VERSION 5.8 ;
BUSBITCHARS "[]" ;
DIVIDERCHAR "/" ;
UNITS
    DATABASE MICRONS 1000 ;
END UNITS

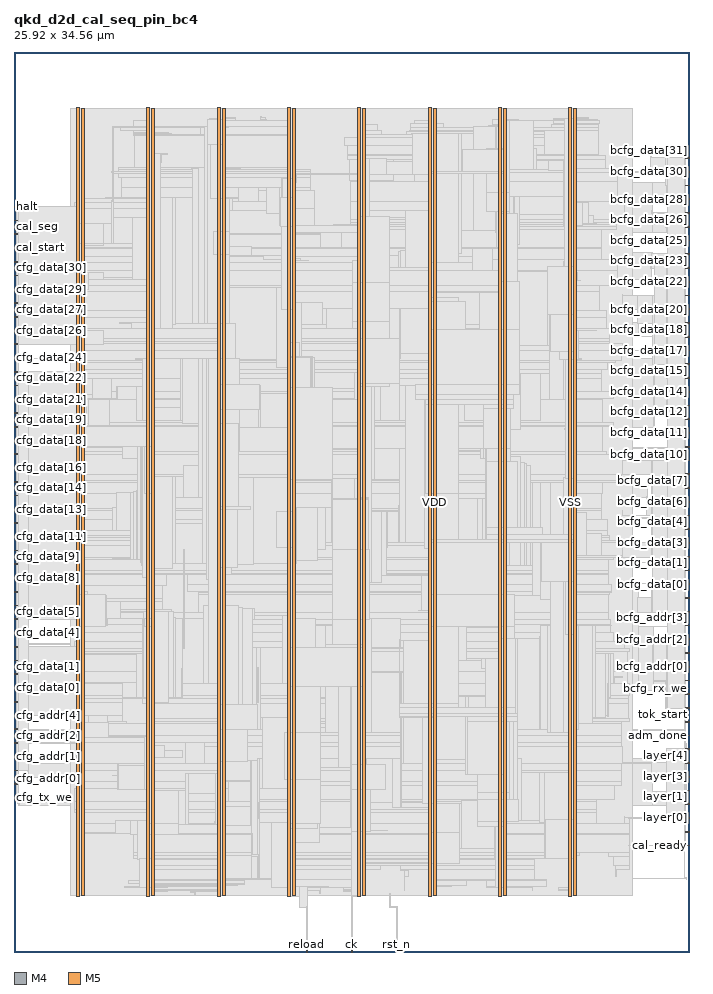
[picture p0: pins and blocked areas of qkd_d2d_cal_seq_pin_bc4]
MACRO qkd_d2d_cal_seq_pin_bc4
  FOREIGN qkd_d2d_cal_seq_pin_bc4 0 0 ;
  CLASS BLOCK ;
  SIZE 25.92 BY 34.56 ;
  PIN adm_done
    DIRECTION OUTPUT ;
    USE SIGNAL ;
    PORT
      LAYER M4 ;
        RECT  25.776 8.304 25.92 8.328 ;
    END
  END adm_done
  PIN bcfg_addr[0]
    DIRECTION INPUT ;
    USE SIGNAL ;
    PORT
      LAYER M4 ;
        RECT  25.776 10.944 25.92 10.968 ;
    END
  END bcfg_addr[0]
  PIN bcfg_addr[1]
    DIRECTION INPUT ;
    USE SIGNAL ;
    PORT
      LAYER M4 ;
        RECT  25.776 11.472 25.92 11.496 ;
    END
  END bcfg_addr[1]
  PIN bcfg_addr[2]
    DIRECTION INPUT ;
    USE SIGNAL ;
    PORT
      LAYER M4 ;
        RECT  25.776 12 25.92 12.024 ;
    END
  END bcfg_addr[2]
  PIN bcfg_addr[3]
    DIRECTION INPUT ;
    USE SIGNAL ;
    PORT
      LAYER M4 ;
        RECT  25.776 12.528 25.92 12.552 ;
    END
  END bcfg_addr[3]
  PIN bcfg_addr[4]
    DIRECTION INPUT ;
    USE SIGNAL ;
    PORT
      LAYER M4 ;
        RECT  25.776 13.056 25.92 13.08 ;
    END
  END bcfg_addr[4]
  PIN bcfg_addr[5]
    DIRECTION INPUT ;
    USE SIGNAL ;
    PORT
      LAYER M4 ;
        RECT  25.776 13.584 25.92 13.608 ;
    END
  END bcfg_addr[5]
  PIN bcfg_data[0]
    DIRECTION INPUT ;
    USE SIGNAL ;
    PORT
      LAYER M4 ;
        RECT  25.776 14.112 25.92 14.136 ;
    END
  END bcfg_data[0]
  PIN bcfg_data[10]
    DIRECTION INPUT ;
    USE SIGNAL ;
    PORT
      LAYER M4 ;
        RECT  25.776 19.392 25.92 19.416 ;
    END
  END bcfg_data[10]
  PIN bcfg_data[11]
    DIRECTION INPUT ;
    USE SIGNAL ;
    PORT
      LAYER M4 ;
        RECT  25.776 19.92 25.92 19.944 ;
    END
  END bcfg_data[11]
  PIN bcfg_data[12]
    DIRECTION INPUT ;
    USE SIGNAL ;
    PORT
      LAYER M4 ;
        RECT  25.776 20.448 25.92 20.472 ;
    END
  END bcfg_data[12]
  PIN bcfg_data[13]
    DIRECTION INPUT ;
    USE SIGNAL ;
    PORT
      LAYER M4 ;
        RECT  25.776 20.976 25.92 21 ;
    END
  END bcfg_data[13]
  PIN bcfg_data[14]
    DIRECTION INPUT ;
    USE SIGNAL ;
    PORT
      LAYER M4 ;
        RECT  25.776 21.504 25.92 21.528 ;
    END
  END bcfg_data[14]
  PIN bcfg_data[15]
    DIRECTION INPUT ;
    USE SIGNAL ;
    PORT
      LAYER M4 ;
        RECT  25.776 22.032 25.92 22.056 ;
    END
  END bcfg_data[15]
  PIN bcfg_data[16]
    DIRECTION INPUT ;
    USE SIGNAL ;
    PORT
      LAYER M4 ;
        RECT  25.776 22.56 25.92 22.584 ;
    END
  END bcfg_data[16]
  PIN bcfg_data[17]
    DIRECTION INPUT ;
    USE SIGNAL ;
    PORT
      LAYER M4 ;
        RECT  25.776 23.088 25.92 23.112 ;
    END
  END bcfg_data[17]
  PIN bcfg_data[18]
    DIRECTION INPUT ;
    USE SIGNAL ;
    PORT
      LAYER M4 ;
        RECT  25.776 23.616 25.92 23.64 ;
    END
  END bcfg_data[18]
  PIN bcfg_data[19]
    DIRECTION INPUT ;
    USE SIGNAL ;
    PORT
      LAYER M4 ;
        RECT  25.776 24.144 25.92 24.168 ;
    END
  END bcfg_data[19]
  PIN bcfg_data[1]
    DIRECTION INPUT ;
    USE SIGNAL ;
    PORT
      LAYER M4 ;
        RECT  25.776 14.64 25.92 14.664 ;
    END
  END bcfg_data[1]
  PIN bcfg_data[20]
    DIRECTION INPUT ;
    USE SIGNAL ;
    PORT
      LAYER M4 ;
        RECT  25.776 24.672 25.92 24.696 ;
    END
  END bcfg_data[20]
  PIN bcfg_data[21]
    DIRECTION INPUT ;
    USE SIGNAL ;
    PORT
      LAYER M4 ;
        RECT  25.776 25.2 25.92 25.224 ;
    END
  END bcfg_data[21]
  PIN bcfg_data[22]
    DIRECTION INPUT ;
    USE SIGNAL ;
    PORT
      LAYER M4 ;
        RECT  25.776 25.728 25.92 25.752 ;
    END
  END bcfg_data[22]
  PIN bcfg_data[23]
    DIRECTION INPUT ;
    USE SIGNAL ;
    PORT
      LAYER M4 ;
        RECT  25.776 26.256 25.92 26.28 ;
    END
  END bcfg_data[23]
  PIN bcfg_data[24]
    DIRECTION INPUT ;
    USE SIGNAL ;
    PORT
      LAYER M4 ;
        RECT  25.776 26.784 25.92 26.808 ;
    END
  END bcfg_data[24]
  PIN bcfg_data[25]
    DIRECTION INPUT ;
    USE SIGNAL ;
    PORT
      LAYER M4 ;
        RECT  25.776 27.312 25.92 27.336 ;
    END
  END bcfg_data[25]
  PIN bcfg_data[26]
    DIRECTION INPUT ;
    USE SIGNAL ;
    PORT
      LAYER M4 ;
        RECT  25.776 27.84 25.92 27.864 ;
    END
  END bcfg_data[26]
  PIN bcfg_data[27]
    DIRECTION INPUT ;
    USE SIGNAL ;
    PORT
      LAYER M4 ;
        RECT  25.776 28.368 25.92 28.392 ;
    END
  END bcfg_data[27]
  PIN bcfg_data[28]
    DIRECTION INPUT ;
    USE SIGNAL ;
    PORT
      LAYER M4 ;
        RECT  25.776 28.896 25.92 28.92 ;
    END
  END bcfg_data[28]
  PIN bcfg_data[29]
    DIRECTION INPUT ;
    USE SIGNAL ;
    PORT
      LAYER M4 ;
        RECT  25.776 29.424 25.92 29.448 ;
    END
  END bcfg_data[29]
  PIN bcfg_data[2]
    DIRECTION INPUT ;
    USE SIGNAL ;
    PORT
      LAYER M4 ;
        RECT  25.776 15.168 25.92 15.192 ;
    END
  END bcfg_data[2]
  PIN bcfg_data[30]
    DIRECTION INPUT ;
    USE SIGNAL ;
    PORT
      LAYER M4 ;
        RECT  25.776 29.952 25.92 29.976 ;
    END
  END bcfg_data[30]
  PIN bcfg_data[31]
    DIRECTION INPUT ;
    USE SIGNAL ;
    PORT
      LAYER M4 ;
        RECT  25.776 30.48 25.92 30.504 ;
    END
  END bcfg_data[31]
  PIN bcfg_data[3]
    DIRECTION INPUT ;
    USE SIGNAL ;
    PORT
      LAYER M4 ;
        RECT  25.776 15.696 25.92 15.72 ;
    END
  END bcfg_data[3]
  PIN bcfg_data[4]
    DIRECTION INPUT ;
    USE SIGNAL ;
    PORT
      LAYER M4 ;
        RECT  25.776 16.224 25.92 16.248 ;
    END
  END bcfg_data[4]
  PIN bcfg_data[5]
    DIRECTION INPUT ;
    USE SIGNAL ;
    PORT
      LAYER M4 ;
        RECT  25.776 16.752 25.92 16.776 ;
    END
  END bcfg_data[5]
  PIN bcfg_data[6]
    DIRECTION INPUT ;
    USE SIGNAL ;
    PORT
      LAYER M4 ;
        RECT  25.776 17.28 25.92 17.304 ;
    END
  END bcfg_data[6]
  PIN bcfg_data[7]
    DIRECTION INPUT ;
    USE SIGNAL ;
    PORT
      LAYER M4 ;
        RECT  25.776 17.808 25.92 17.832 ;
    END
  END bcfg_data[7]
  PIN bcfg_data[8]
    DIRECTION INPUT ;
    USE SIGNAL ;
    PORT
      LAYER M4 ;
        RECT  25.776 18.336 25.92 18.36 ;
    END
  END bcfg_data[8]
  PIN bcfg_data[9]
    DIRECTION INPUT ;
    USE SIGNAL ;
    PORT
      LAYER M4 ;
        RECT  25.776 18.864 25.92 18.888 ;
    END
  END bcfg_data[9]
  PIN bcfg_rx_we
    DIRECTION INPUT ;
    USE SIGNAL ;
    PORT
      LAYER M4 ;
        RECT  25.776 10.416 25.92 10.44 ;
    END
  END bcfg_rx_we
  PIN bcfg_tx_we
    DIRECTION INPUT ;
    USE SIGNAL ;
    PORT
      LAYER M4 ;
        RECT  25.776 9.888 25.92 9.912 ;
    END
  END bcfg_tx_we
  PIN cal_ready
    DIRECTION OUTPUT ;
    USE SIGNAL ;
    PORT
      LAYER M4 ;
        RECT  25.776 4.08 25.92 4.104 ;
    END
  END cal_ready
  PIN cal_seg
    DIRECTION OUTPUT ;
    USE SIGNAL ;
    PORT
      LAYER M4 ;
        RECT  0 27.552 0.144 27.576 ;
    END
  END cal_seg
  PIN cal_start
    DIRECTION OUTPUT ;
    USE SIGNAL ;
    PORT
      LAYER M4 ;
        RECT  0 27.024 0.144 27.048 ;
    END
  END cal_start
  PIN cfg_addr[0]
    DIRECTION OUTPUT ;
    USE SIGNAL ;
    PORT
      LAYER M4 ;
        RECT  0 6.96 0.144 6.984 ;
    END
  END cfg_addr[0]
  PIN cfg_addr[1]
    DIRECTION OUTPUT ;
    USE SIGNAL ;
    PORT
      LAYER M4 ;
        RECT  0 7.488 0.144 7.512 ;
    END
  END cfg_addr[1]
  PIN cfg_addr[2]
    DIRECTION OUTPUT ;
    USE SIGNAL ;
    PORT
      LAYER M4 ;
        RECT  0 8.016 0.144 8.04 ;
    END
  END cfg_addr[2]
  PIN cfg_addr[3]
    DIRECTION OUTPUT ;
    USE SIGNAL ;
    PORT
      LAYER M4 ;
        RECT  0 8.544 0.144 8.568 ;
    END
  END cfg_addr[3]
  PIN cfg_addr[4]
    DIRECTION OUTPUT ;
    USE SIGNAL ;
    PORT
      LAYER M4 ;
        RECT  0 9.072 0.144 9.096 ;
    END
  END cfg_addr[4]
  PIN cfg_addr[5]
    DIRECTION OUTPUT ;
    USE SIGNAL ;
    PORT
      LAYER M4 ;
        RECT  0 9.6 0.144 9.624 ;
    END
  END cfg_addr[5]
  PIN cfg_data[0]
    DIRECTION OUTPUT ;
    USE SIGNAL ;
    PORT
      LAYER M4 ;
        RECT  0 10.128 0.144 10.152 ;
    END
  END cfg_data[0]
  PIN cfg_data[10]
    DIRECTION OUTPUT ;
    USE SIGNAL ;
    PORT
      LAYER M4 ;
        RECT  0 15.408 0.144 15.432 ;
    END
  END cfg_data[10]
  PIN cfg_data[11]
    DIRECTION OUTPUT ;
    USE SIGNAL ;
    PORT
      LAYER M4 ;
        RECT  0 15.936 0.144 15.96 ;
    END
  END cfg_data[11]
  PIN cfg_data[12]
    DIRECTION OUTPUT ;
    USE SIGNAL ;
    PORT
      LAYER M4 ;
        RECT  0 16.464 0.144 16.488 ;
    END
  END cfg_data[12]
  PIN cfg_data[13]
    DIRECTION OUTPUT ;
    USE SIGNAL ;
    PORT
      LAYER M4 ;
        RECT  0 16.992 0.144 17.016 ;
    END
  END cfg_data[13]
  PIN cfg_data[14]
    DIRECTION OUTPUT ;
    USE SIGNAL ;
    PORT
      LAYER M4 ;
        RECT  0 17.52 0.144 17.544 ;
    END
  END cfg_data[14]
  PIN cfg_data[15]
    DIRECTION OUTPUT ;
    USE SIGNAL ;
    PORT
      LAYER M4 ;
        RECT  0 18.048 0.144 18.072 ;
    END
  END cfg_data[15]
  PIN cfg_data[16]
    DIRECTION OUTPUT ;
    USE SIGNAL ;
    PORT
      LAYER M4 ;
        RECT  0 18.576 0.144 18.6 ;
    END
  END cfg_data[16]
  PIN cfg_data[17]
    DIRECTION OUTPUT ;
    USE SIGNAL ;
    PORT
      LAYER M4 ;
        RECT  0 19.104 0.144 19.128 ;
    END
  END cfg_data[17]
  PIN cfg_data[18]
    DIRECTION OUTPUT ;
    USE SIGNAL ;
    PORT
      LAYER M4 ;
        RECT  0 19.632 0.144 19.656 ;
    END
  END cfg_data[18]
  PIN cfg_data[19]
    DIRECTION OUTPUT ;
    USE SIGNAL ;
    PORT
      LAYER M4 ;
        RECT  0 20.16 0.144 20.184 ;
    END
  END cfg_data[19]
  PIN cfg_data[1]
    DIRECTION OUTPUT ;
    USE SIGNAL ;
    PORT
      LAYER M4 ;
        RECT  0 10.656 0.144 10.68 ;
    END
  END cfg_data[1]
  PIN cfg_data[20]
    DIRECTION OUTPUT ;
    USE SIGNAL ;
    PORT
      LAYER M4 ;
        RECT  0 20.688 0.144 20.712 ;
    END
  END cfg_data[20]
  PIN cfg_data[21]
    DIRECTION OUTPUT ;
    USE SIGNAL ;
    PORT
      LAYER M4 ;
        RECT  0 21.216 0.144 21.24 ;
    END
  END cfg_data[21]
  PIN cfg_data[22]
    DIRECTION OUTPUT ;
    USE SIGNAL ;
    PORT
      LAYER M4 ;
        RECT  0 21.744 0.144 21.768 ;
    END
  END cfg_data[22]
  PIN cfg_data[23]
    DIRECTION OUTPUT ;
    USE SIGNAL ;
    PORT
      LAYER M4 ;
        RECT  0 22.272 0.144 22.296 ;
    END
  END cfg_data[23]
  PIN cfg_data[24]
    DIRECTION OUTPUT ;
    USE SIGNAL ;
    PORT
      LAYER M4 ;
        RECT  0 22.8 0.144 22.824 ;
    END
  END cfg_data[24]
  PIN cfg_data[25]
    DIRECTION OUTPUT ;
    USE SIGNAL ;
    PORT
      LAYER M4 ;
        RECT  0 23.328 0.144 23.352 ;
    END
  END cfg_data[25]
  PIN cfg_data[26]
    DIRECTION OUTPUT ;
    USE SIGNAL ;
    PORT
      LAYER M4 ;
        RECT  0 23.856 0.144 23.88 ;
    END
  END cfg_data[26]
  PIN cfg_data[27]
    DIRECTION OUTPUT ;
    USE SIGNAL ;
    PORT
      LAYER M4 ;
        RECT  0 24.384 0.144 24.408 ;
    END
  END cfg_data[27]
  PIN cfg_data[28]
    DIRECTION OUTPUT ;
    USE SIGNAL ;
    PORT
      LAYER M4 ;
        RECT  0 24.912 0.144 24.936 ;
    END
  END cfg_data[28]
  PIN cfg_data[29]
    DIRECTION OUTPUT ;
    USE SIGNAL ;
    PORT
      LAYER M4 ;
        RECT  0 25.44 0.144 25.464 ;
    END
  END cfg_data[29]
  PIN cfg_data[2]
    DIRECTION OUTPUT ;
    USE SIGNAL ;
    PORT
      LAYER M4 ;
        RECT  0 11.184 0.144 11.208 ;
    END
  END cfg_data[2]
  PIN cfg_data[30]
    DIRECTION OUTPUT ;
    USE SIGNAL ;
    PORT
      LAYER M4 ;
        RECT  0 25.968 0.144 25.992 ;
    END
  END cfg_data[30]
  PIN cfg_data[31]
    DIRECTION OUTPUT ;
    USE SIGNAL ;
    PORT
      LAYER M4 ;
        RECT  0 26.496 0.144 26.52 ;
    END
  END cfg_data[31]
  PIN cfg_data[3]
    DIRECTION OUTPUT ;
    USE SIGNAL ;
    PORT
      LAYER M4 ;
        RECT  0 11.712 0.144 11.736 ;
    END
  END cfg_data[3]
  PIN cfg_data[4]
    DIRECTION OUTPUT ;
    USE SIGNAL ;
    PORT
      LAYER M4 ;
        RECT  0 12.24 0.144 12.264 ;
    END
  END cfg_data[4]
  PIN cfg_data[5]
    DIRECTION OUTPUT ;
    USE SIGNAL ;
    PORT
      LAYER M4 ;
        RECT  0 12.768 0.144 12.792 ;
    END
  END cfg_data[5]
  PIN cfg_data[6]
    DIRECTION OUTPUT ;
    USE SIGNAL ;
    PORT
      LAYER M4 ;
        RECT  0 13.296 0.144 13.32 ;
    END
  END cfg_data[6]
  PIN cfg_data[7]
    DIRECTION OUTPUT ;
    USE SIGNAL ;
    PORT
      LAYER M4 ;
        RECT  0 13.824 0.144 13.848 ;
    END
  END cfg_data[7]
  PIN cfg_data[8]
    DIRECTION OUTPUT ;
    USE SIGNAL ;
    PORT
      LAYER M4 ;
        RECT  0 14.352 0.144 14.376 ;
    END
  END cfg_data[8]
  PIN cfg_data[9]
    DIRECTION OUTPUT ;
    USE SIGNAL ;
    PORT
      LAYER M4 ;
        RECT  0 14.88 0.144 14.904 ;
    END
  END cfg_data[9]
  PIN cfg_rx_we
    DIRECTION OUTPUT ;
    USE SIGNAL ;
    PORT
      LAYER M4 ;
        RECT  0 6.432 0.144 6.456 ;
    END
  END cfg_rx_we
  PIN cfg_tx_we
    DIRECTION OUTPUT ;
    USE SIGNAL ;
    PORT
      LAYER M4 ;
        RECT  0 5.904 0.144 5.928 ;
    END
  END cfg_tx_we
  PIN ck
    DIRECTION INPUT ;
    USE SIGNAL ;
    PORT
      LAYER M5 ;
        RECT  12.96 0 12.984 0.144 ;
    END
  END ck
  PIN epoch_go
    DIRECTION INPUT ;
    USE SIGNAL ;
    PORT
      LAYER M4 ;
        RECT  0 28.08 0.144 28.104 ;
    END
  END epoch_go
  PIN fault
    DIRECTION OUTPUT ;
    USE SIGNAL ;
    PORT
      LAYER M4 ;
        RECT  25.776 9.36 25.92 9.384 ;
    END
  END fault
  PIN halt
    DIRECTION INPUT ;
    USE SIGNAL ;
    PORT
      LAYER M4 ;
        RECT  0 28.608 0.144 28.632 ;
    END
  END halt
  PIN layer[0]
    DIRECTION OUTPUT ;
    USE SIGNAL ;
    PORT
      LAYER M4 ;
        RECT  25.776 5.136 25.92 5.16 ;
    END
  END layer[0]
  PIN layer[1]
    DIRECTION OUTPUT ;
    USE SIGNAL ;
    PORT
      LAYER M4 ;
        RECT  25.776 5.664 25.92 5.688 ;
    END
  END layer[1]
  PIN layer[2]
    DIRECTION OUTPUT ;
    USE SIGNAL ;
    PORT
      LAYER M4 ;
        RECT  25.776 6.192 25.92 6.216 ;
    END
  END layer[2]
  PIN layer[3]
    DIRECTION OUTPUT ;
    USE SIGNAL ;
    PORT
      LAYER M4 ;
        RECT  25.776 6.72 25.92 6.744 ;
    END
  END layer[3]
  PIN layer[4]
    DIRECTION OUTPUT ;
    USE SIGNAL ;
    PORT
      LAYER M4 ;
        RECT  25.776 7.248 25.92 7.272 ;
    END
  END layer[4]
  PIN layer[5]
    DIRECTION OUTPUT ;
    USE SIGNAL ;
    PORT
      LAYER M4 ;
        RECT  25.776 7.776 25.92 7.8 ;
    END
  END layer[5]
  PIN reload
    DIRECTION INPUT ;
    USE SIGNAL ;
    PORT
      LAYER M5 ;
        RECT  11.232 0 11.256 0.144 ;
    END
  END reload
  PIN rst_n
    DIRECTION INPUT ;
    USE SIGNAL ;
    PORT
      LAYER M5 ;
        RECT  14.688 0 14.712 0.144 ;
    END
  END rst_n
  PIN running
    DIRECTION OUTPUT ;
    USE SIGNAL ;
    PORT
      LAYER M4 ;
        RECT  25.776 4.608 25.92 4.632 ;
    END
  END running
  PIN tok_start
    DIRECTION OUTPUT ;
    USE SIGNAL ;
    PORT
      LAYER M4 ;
        RECT  25.776 8.832 25.92 8.856 ;
    END
  END tok_start
  PIN VDD
    DIRECTION INOUT ;
    USE POWER ;
    PORT
      LAYER M5 ;
        RECT  21.492 2.151 21.612 32.409 ;
        RECT  18.792 2.151 18.912 32.409 ;
        RECT  16.092 2.151 16.212 32.409 ;
        RECT  13.392 2.151 13.512 32.409 ;
        RECT  10.692 2.151 10.812 32.409 ;
        RECT  7.992 2.151 8.112 32.409 ;
        RECT  5.292 2.151 5.412 32.409 ;
        RECT  2.592 2.151 2.712 32.409 ;
    END
  END VDD
  PIN VSS
    DIRECTION INOUT ;
    USE GROUND ;
    PORT
      LAYER M5 ;
        RECT  21.3 2.137 21.42 32.423 ;
        RECT  18.6 2.137 18.72 32.423 ;
        RECT  15.9 2.137 16.02 32.423 ;
        RECT  13.2 2.137 13.32 32.423 ;
        RECT  10.5 2.137 10.62 32.423 ;
        RECT  7.8 2.137 7.92 32.423 ;
        RECT  5.1 2.137 5.22 32.423 ;
        RECT  2.4 2.137 2.52 32.423 ;
    END
  END VSS
  OBS
    LAYER RVTN ;
     RECT  2.16 2.16 23.76 2.295 ;
     RECT  2.16 2.565 23.76 2.835 ;
     RECT  2.16 3.105 23.76 3.375 ;
     RECT  2.16 3.645 23.76 3.915 ;
     RECT  2.16 4.185 23.76 4.455 ;
     RECT  2.16 4.725 23.76 4.995 ;
     RECT  2.16 5.265 23.76 5.535 ;
     RECT  2.16 5.805 23.76 6.075 ;
     RECT  2.16 6.345 23.76 6.615 ;
     RECT  2.16 6.885 23.76 7.155 ;
     RECT  2.16 7.425 23.76 7.695 ;
     RECT  2.16 7.965 23.76 8.235 ;
     RECT  2.16 8.505 23.76 8.775 ;
     RECT  2.16 9.045 23.76 9.315 ;
     RECT  2.16 9.585 23.76 9.855 ;
     RECT  2.16 10.125 23.76 10.395 ;
     RECT  2.16 10.665 23.76 10.935 ;
     RECT  2.16 11.205 23.76 11.475 ;
     RECT  2.16 11.745 23.76 12.015 ;
     RECT  2.16 12.285 23.76 12.555 ;
     RECT  2.16 12.825 23.76 13.095 ;
     RECT  2.16 13.365 23.76 13.635 ;
     RECT  2.16 13.905 23.76 14.175 ;
     RECT  2.16 14.445 23.76 14.715 ;
     RECT  2.16 14.985 23.76 15.255 ;
     RECT  2.16 15.525 23.76 15.795 ;
     RECT  2.16 16.065 23.76 16.335 ;
     RECT  2.16 16.605 23.76 16.875 ;
     RECT  2.16 17.145 23.76 17.415 ;
     RECT  2.16 17.685 23.76 17.955 ;
     RECT  2.16 18.225 23.76 18.495 ;
     RECT  2.16 18.765 23.76 19.035 ;
     RECT  2.16 19.305 23.76 19.575 ;
     RECT  2.16 19.845 23.76 20.115 ;
     RECT  2.16 20.385 23.76 20.655 ;
     RECT  2.16 20.925 23.76 21.195 ;
     RECT  2.16 21.465 23.76 21.735 ;
     RECT  2.16 22.005 23.76 22.275 ;
     RECT  2.16 22.545 23.76 22.815 ;
     RECT  2.16 23.085 23.76 23.355 ;
     RECT  2.16 23.625 23.76 23.895 ;
     RECT  2.16 24.165 23.76 24.435 ;
     RECT  2.16 24.705 23.76 24.975 ;
     RECT  2.16 25.245 23.76 25.515 ;
     RECT  2.16 25.785 23.76 26.055 ;
     RECT  2.16 26.325 23.76 26.595 ;
     RECT  2.16 26.865 23.76 27.135 ;
     RECT  2.16 27.405 23.76 27.675 ;
     RECT  2.16 27.945 23.76 28.215 ;
     RECT  2.16 28.485 23.76 28.755 ;
     RECT  2.16 29.025 23.76 29.295 ;
     RECT  2.16 29.565 23.76 29.835 ;
     RECT  2.16 30.105 23.76 30.375 ;
     RECT  2.16 30.645 23.76 30.915 ;
     RECT  2.16 31.185 23.76 31.455 ;
     RECT  2.16 31.725 23.76 31.995 ;
     RECT  2.16 32.265 23.76 32.4 ;
    LAYER RVTP ;
     RECT  2.16 2.295 23.76 2.565 ;
     RECT  2.16 2.835 23.76 3.105 ;
     RECT  2.16 3.375 23.76 3.645 ;
     RECT  2.16 3.915 23.76 4.185 ;
     RECT  2.16 4.455 23.76 4.725 ;
     RECT  2.16 4.995 23.76 5.265 ;
     RECT  2.16 5.535 23.76 5.805 ;
     RECT  2.16 6.075 23.76 6.345 ;
     RECT  2.16 6.615 23.76 6.885 ;
     RECT  2.16 7.155 23.76 7.425 ;
     RECT  2.16 7.695 23.76 7.965 ;
     RECT  2.16 8.235 23.76 8.505 ;
     RECT  2.16 8.775 23.76 9.045 ;
     RECT  2.16 9.315 23.76 9.585 ;
     RECT  2.16 9.855 23.76 10.125 ;
     RECT  2.16 10.395 23.76 10.665 ;
     RECT  2.16 10.935 23.76 11.205 ;
     RECT  2.16 11.475 23.76 11.745 ;
     RECT  2.16 12.015 23.76 12.285 ;
     RECT  2.16 12.555 23.76 12.825 ;
     RECT  2.16 13.095 23.76 13.365 ;
     RECT  2.16 13.635 23.76 13.905 ;
     RECT  2.16 14.175 23.76 14.445 ;
     RECT  2.16 14.715 23.76 14.985 ;
     RECT  2.16 15.255 23.76 15.525 ;
     RECT  2.16 15.795 23.76 16.065 ;
     RECT  2.16 16.335 23.76 16.605 ;
     RECT  2.16 16.875 23.76 17.145 ;
     RECT  2.16 17.415 23.76 17.685 ;
     RECT  2.16 17.955 23.76 18.225 ;
     RECT  2.16 18.495 23.76 18.765 ;
     RECT  2.16 19.035 23.76 19.305 ;
     RECT  2.16 19.575 23.76 19.845 ;
     RECT  2.16 20.115 23.76 20.385 ;
     RECT  2.16 20.655 23.76 20.925 ;
     RECT  2.16 21.195 23.76 21.465 ;
     RECT  2.16 21.735 23.76 22.005 ;
     RECT  2.16 22.275 23.76 22.545 ;
     RECT  2.16 22.815 23.76 23.085 ;
     RECT  2.16 23.355 23.76 23.625 ;
     RECT  2.16 23.895 23.76 24.165 ;
     RECT  2.16 24.435 23.76 24.705 ;
     RECT  2.16 24.975 23.76 25.245 ;
     RECT  2.16 25.515 23.76 25.785 ;
     RECT  2.16 26.055 23.76 26.325 ;
     RECT  2.16 26.595 23.76 26.865 ;
     RECT  2.16 27.135 23.76 27.405 ;
     RECT  2.16 27.675 23.76 27.945 ;
     RECT  2.16 28.215 23.76 28.485 ;
     RECT  2.16 28.755 23.76 29.025 ;
     RECT  2.16 29.295 23.76 29.565 ;
     RECT  2.16 29.835 23.76 30.105 ;
     RECT  2.16 30.375 23.76 30.645 ;
     RECT  2.16 30.915 23.76 31.185 ;
     RECT  2.16 31.455 23.76 31.725 ;
     RECT  2.16 31.995 23.76 32.265 ;
    LAYER M1 ;
     RECT  2.16 2.151 23.76 32.409 ;
    LAYER M2 ;
     RECT  0.139 5.706 0.175 5.724 ;
     RECT  0.175 5.616 2.16 5.724 ;
     RECT  0.535 6.696 2.16 7.254 ;
     RECT  0.535 8.514 2.16 8.532 ;
     RECT  0.535 11.826 2.16 11.844 ;
     RECT  0.139 22.788 2.16 22.806 ;
     RECT  2.16 2.151 23.76 32.409 ;
     RECT  23.76 10.026 23.963 14.166 ;
     RECT  23.76 23.634 23.963 24.156 ;
     RECT  23.76 17.46 24.323 17.946 ;
     RECT  23.76 25.83 24.467 26.856 ;
     RECT  23.76 30.618 24.467 30.636 ;
     RECT  23.76 5.616 24.503 7.416 ;
     RECT  23.963 14.148 24.503 14.166 ;
     RECT  23.76 16.65 24.503 16.668 ;
     RECT  24.323 17.928 24.503 17.946 ;
     RECT  24.467 26.838 24.503 26.856 ;
     RECT  23.76 27.612 24.503 29.556 ;
     RECT  23.963 10.026 24.539 12.51 ;
     RECT  23.76 14.958 24.539 14.976 ;
     RECT  23.76 20.16 24.539 22.806 ;
     RECT  23.963 23.634 24.539 23.652 ;
     RECT  24.539 11.25 24.575 11.268 ;
     RECT  24.539 20.16 24.611 22.23 ;
     RECT  24.467 25.83 24.611 25.848 ;
     RECT  24.539 10.026 25.043 10.386 ;
     RECT  24.503 27.612 25.043 27.936 ;
     RECT  24.503 28.962 25.043 29.556 ;
     RECT  24.503 5.616 25.079 6.174 ;
     RECT  24.503 7.398 25.079 7.416 ;
     RECT  25.043 10.368 25.079 10.386 ;
     RECT  24.611 20.7 25.079 22.23 ;
     RECT  24.539 12.492 25.115 12.51 ;
     RECT  23.76 19.35 25.115 19.368 ;
     RECT  25.079 20.7 25.115 20.718 ;
     RECT  25.079 21.744 25.115 21.762 ;
     RECT  25.043 27.612 25.115 27.63 ;
     RECT  25.043 28.962 25.115 28.98 ;
     RECT  23.76 2.808 25.735 2.826 ;
     RECT  23.76 8.514 25.763 8.532 ;
     RECT  25.735 2.808 25.835 2.862 ;
     RECT  25.079 5.886 25.835 5.904 ;
    LAYER M3 ;
     RECT  10.98 1.723 10.998 2.143 ;
     RECT  14.436 1.723 14.454 2.255 ;
     RECT  6.948 2.191 6.966 2.299 ;
     RECT  5.115 2.143 5.205 2.335 ;
     RECT  6.768 2.299 6.966 2.335 ;
     RECT  7.815 2.143 7.905 2.335 ;
     RECT  13.215 2.143 13.305 2.335 ;
     RECT  5.115 2.335 5.886 2.371 ;
     RECT  6.768 2.335 7.905 2.371 ;
     RECT  10.515 2.143 10.998 2.371 ;
     RECT  11.736 2.263 11.754 2.371 ;
     RECT  12.636 2.335 13.305 2.371 ;
     RECT  21.315 2.143 21.405 2.371 ;
     RECT  2.415 2.143 2.505 2.413 ;
     RECT  5.115 2.371 7.974 2.413 ;
     RECT  12.636 2.371 13.374 2.413 ;
     RECT  15.915 2.143 16.005 2.413 ;
     RECT  18.615 2.143 18.705 2.413 ;
     RECT  20.916 2.371 21.405 2.413 ;
     RECT  18.615 2.413 18.897 2.461 ;
     RECT  19.908 2.371 19.926 2.488 ;
     RECT  20.916 2.413 21.597 2.489 ;
     RECT  10.515 2.371 11.754 2.491 ;
     RECT  12.636 2.413 13.497 2.491 ;
     RECT  5.115 2.413 8.097 2.497 ;
     RECT  18.144 2.461 18.897 2.497 ;
     RECT  19.62 2.488 19.926 2.497 ;
     RECT  4.248 2.491 4.266 2.531 ;
     RECT  15.915 2.413 16.197 2.533 ;
     RECT  5.004 2.497 8.097 2.569 ;
     RECT  15.915 2.533 16.794 2.569 ;
     RECT  5.004 2.569 8.586 2.605 ;
     RECT  5.004 2.605 8.838 2.641 ;
     RECT  15.915 2.569 17.37 2.731 ;
     RECT  18.144 2.497 20.466 2.731 ;
     RECT  4.392 2.641 8.838 2.759 ;
     RECT  5.004 2.759 8.838 2.795 ;
     RECT  15.915 2.731 20.466 2.795 ;
     RECT  5.115 2.795 8.838 2.803 ;
     RECT  9.9 2.491 13.497 2.803 ;
     RECT  25.812 2.803 25.83 2.839 ;
     RECT  25.74 2.839 25.83 2.867 ;
     RECT  14.976 2.371 14.994 2.911 ;
     RECT  14.976 2.911 15.138 3.145 ;
     RECT  5.115 2.803 13.497 3.181 ;
     RECT  14.832 3.145 15.138 3.181 ;
     RECT  15.915 2.795 19.998 3.181 ;
     RECT  23.112 2.911 23.13 3.181 ;
     RECT  5.115 3.181 14.058 3.307 ;
     RECT  14.832 3.181 19.998 3.307 ;
     RECT  23.112 3.181 23.634 3.307 ;
     RECT  21.315 2.489 21.597 3.451 ;
     RECT  5.115 3.307 19.998 3.547 ;
     RECT  4.788 3.547 19.998 3.577 ;
     RECT  21.276 3.451 21.597 3.604 ;
     RECT  23.04 3.307 23.634 3.685 ;
     RECT  4.572 3.577 20.466 3.721 ;
     RECT  21.24 3.604 21.597 3.721 ;
     RECT  4.572 3.721 21.726 3.811 ;
     RECT  22.824 3.685 23.634 3.811 ;
     RECT  4.572 3.811 23.634 4.495 ;
     RECT  2.415 2.413 2.697 4.555 ;
     RECT  4.5 4.495 23.634 4.555 ;
     RECT  25.74 2.867 25.758 4.637 ;
     RECT  2.415 4.555 23.634 4.919 ;
     RECT  23.436 4.919 23.634 5.165 ;
     RECT  23.436 5.165 23.454 5.189 ;
     RECT  2.415 4.919 22.374 5.341 ;
     RECT  2.304 5.341 22.374 5.459 ;
     RECT  0.18 5.611 0.198 5.701 ;
     RECT  2.34 5.459 22.374 5.765 ;
     RECT  9.108 5.765 22.374 5.845 ;
     RECT  0.144 5.701 0.198 5.933 ;
     RECT  25.056 5.611 25.074 6.221 ;
     RECT  2.34 5.765 8.226 6.269 ;
     RECT  9.108 5.845 23.058 6.385 ;
     RECT  0.144 5.933 0.162 6.461 ;
     RECT  2.415 6.269 8.226 6.547 ;
     RECT  9.108 6.385 23.31 6.547 ;
     RECT  24.48 6.691 24.498 6.749 ;
     RECT  2.415 6.547 23.31 6.961 ;
     RECT  2.415 6.961 23.346 7.223 ;
     RECT  7.308 7.223 23.346 7.231 ;
     RECT  0.54 6.691 0.558 7.517 ;
     RECT  25.056 7.393 25.074 7.805 ;
     RECT  7.308 7.231 23.382 7.889 ;
     RECT  25.812 5.881 25.83 7.963 ;
     RECT  25.74 7.963 25.83 7.997 ;
     RECT  2.415 7.223 6.57 8.041 ;
     RECT  7.308 7.889 23.346 8.041 ;
     RECT  2.415 8.041 23.346 8.303 ;
     RECT  0.54 8.509 0.558 8.573 ;
     RECT  3.6 8.303 23.346 8.771 ;
     RECT  3.6 8.771 4.338 8.843 ;
     RECT  5.112 8.771 23.346 8.851 ;
     RECT  25.74 7.997 25.758 8.861 ;
     RECT  5.112 8.851 23.634 8.969 ;
     RECT  2.415 8.303 2.862 9.085 ;
     RECT  3.6 8.843 4.158 9.085 ;
     RECT  5.112 8.969 23.598 9.553 ;
     RECT  2.415 9.085 4.158 9.595 ;
     RECT  2.304 9.595 4.158 9.751 ;
     RECT  4.932 9.553 23.598 9.751 ;
     RECT  2.304 9.751 23.598 9.859 ;
     RECT  25.02 9.355 25.038 9.883 ;
     RECT  2.304 9.859 23.634 10.319 ;
     RECT  25.02 9.883 25.074 10.391 ;
     RECT  2.304 10.319 23.562 10.769 ;
     RECT  24.552 10.411 24.57 10.939 ;
     RECT  24.516 10.939 24.57 11.273 ;
     RECT  2.412 10.769 23.562 11.551 ;
     RECT  2.304 11.551 23.634 11.669 ;
     RECT  2.304 11.669 23.454 11.939 ;
     RECT  24.516 11.273 24.534 12.029 ;
     RECT  0.54 11.821 0.558 12.269 ;
     RECT  2.415 11.939 23.022 12.281 ;
     RECT  2.415 12.281 22.914 12.557 ;
     RECT  25.092 12.487 25.11 12.557 ;
     RECT  4.104 12.557 22.914 12.749 ;
     RECT  4.104 12.749 22.842 13.019 ;
     RECT  4.104 13.019 6.102 13.085 ;
     RECT  4.104 13.085 6.066 13.163 ;
     RECT  2.415 12.557 3.294 13.441 ;
     RECT  4.104 13.163 5.706 13.441 ;
     RECT  2.376 13.441 5.706 13.559 ;
     RECT  23.94 13.051 23.958 13.631 ;
     RECT  7.092 13.019 22.842 13.711 ;
     RECT  7.092 13.711 22.878 13.801 ;
     RECT  7.092 13.801 22.95 13.837 ;
     RECT  2.415 13.559 5.706 14.071 ;
     RECT  6.66 13.837 22.95 14.099 ;
     RECT  24.48 14.107 24.498 14.171 ;
     RECT  2.415 14.071 5.85 14.485 ;
     RECT  6.66 14.099 22.842 14.485 ;
     RECT  2.415 14.485 22.842 14.521 ;
     RECT  2.376 14.521 22.842 14.639 ;
     RECT  24.516 14.635 24.534 14.981 ;
     RECT  2.415 14.639 22.842 15.061 ;
     RECT  2.415 15.061 23.022 15.163 ;
     RECT  2.415 15.163 23.382 15.601 ;
     RECT  2.376 15.601 23.382 15.791 ;
     RECT  2.376 15.791 22.878 15.931 ;
     RECT  2.304 15.931 22.878 15.989 ;
     RECT  2.304 15.989 22.806 16.169 ;
     RECT  2.376 16.169 22.806 16.601 ;
     RECT  24.48 16.219 24.498 16.673 ;
     RECT  23.364 16.747 23.382 16.943 ;
     RECT  2.376 16.601 22.554 16.951 ;
     RECT  2.304 16.951 22.554 17.021 ;
     RECT  24.3 17.275 24.318 17.483 ;
     RECT  2.376 17.021 22.554 17.617 ;
     RECT  24.48 17.803 24.498 17.951 ;
     RECT  2.376 17.617 22.59 18.031 ;
     RECT  2.376 18.031 23.274 18.121 ;
     RECT  2.376 18.121 23.346 18.331 ;
     RECT  2.376 18.331 23.382 19.099 ;
     RECT  2.304 19.099 23.382 19.103 ;
     RECT  2.304 19.103 22.734 19.229 ;
     RECT  25.092 19.345 25.11 19.421 ;
     RECT  24.588 19.915 24.606 20.183 ;
     RECT  2.304 19.229 22.59 20.191 ;
     RECT  2.304 20.191 23.022 20.219 ;
     RECT  2.304 20.219 2.862 20.309 ;
     RECT  3.672 20.219 23.022 20.345 ;
     RECT  25.092 20.443 25.11 20.723 ;
     RECT  25.056 20.971 25.074 21.191 ;
     RECT  2.415 20.309 2.862 21.211 ;
     RECT  3.672 20.345 22.59 21.211 ;
     RECT  2.376 21.211 22.59 21.263 ;
     RECT  3.744 21.263 22.59 21.271 ;
     RECT  2.376 21.263 3.006 21.397 ;
     RECT  3.744 21.271 23.022 21.533 ;
     RECT  25.092 21.499 25.11 21.767 ;
     RECT  2.304 21.397 3.006 22.009 ;
     RECT  3.744 21.533 22.554 22.009 ;
     RECT  2.304 22.009 22.554 22.199 ;
     RECT  25.056 22.027 25.074 22.235 ;
     RECT  2.415 22.199 22.554 22.351 ;
     RECT  2.415 22.351 22.806 22.621 ;
     RECT  2.415 22.621 23.094 22.711 ;
     RECT  24.516 22.555 24.534 22.811 ;
     RECT  0.144 22.783 0.162 22.829 ;
     RECT  2.415 22.711 23.346 23.083 ;
     RECT  2.415 23.083 23.382 23.351 ;
     RECT  2.415 23.351 22.878 23.431 ;
     RECT  2.304 23.431 22.878 23.549 ;
     RECT  24.516 23.611 24.534 23.657 ;
     RECT  2.376 23.549 22.878 23.927 ;
     RECT  23.94 24.133 23.958 24.173 ;
     RECT  2.376 23.927 22.77 24.379 ;
     RECT  2.304 24.379 22.77 24.629 ;
     RECT  23.364 24.667 23.382 25.241 ;
     RECT  2.304 24.629 22.482 25.349 ;
     RECT  2.415 25.349 22.482 25.591 ;
     RECT  24.588 25.723 24.606 25.853 ;
     RECT  0.144 25.963 0.162 26.093 ;
     RECT  2.415 25.591 23.166 26.159 ;
     RECT  24.444 26.251 24.462 26.321 ;
     RECT  2.415 26.159 17.622 26.491 ;
     RECT  18.36 26.159 23.166 26.591 ;
     RECT  2.304 26.491 17.622 26.699 ;
     RECT  23.4 26.671 23.418 26.789 ;
     RECT  24.48 26.779 24.498 26.861 ;
     RECT  2.415 26.699 17.622 27.031 ;
     RECT  18.36 26.591 22.554 27.031 ;
     RECT  2.415 27.031 22.554 27.059 ;
     RECT  0.144 27.019 0.162 27.149 ;
     RECT  2.415 27.059 11.754 27.547 ;
     RECT  2.304 27.547 11.754 27.599 ;
     RECT  25.092 27.307 25.11 27.635 ;
     RECT  12.564 27.059 22.554 27.751 ;
     RECT  12.564 27.751 23.13 27.877 ;
     RECT  12.276 27.877 23.13 27.917 ;
     RECT  25.02 27.835 25.038 27.941 ;
     RECT  12.924 27.917 23.13 28.021 ;
     RECT  12.924 28.021 23.634 28.139 ;
     RECT  24.48 28.363 24.498 28.481 ;
     RECT  2.304 27.599 11.538 28.553 ;
     RECT  2.304 28.553 8.622 28.787 ;
     RECT  12.924 28.139 23.454 28.823 ;
     RECT  2.415 28.787 8.622 28.949 ;
     RECT  3.528 28.949 8.622 28.985 ;
     RECT  25.092 28.891 25.11 28.985 ;
     RECT  9.396 28.553 11.538 29.255 ;
     RECT  4.14 28.985 8.622 29.371 ;
     RECT  9.396 29.255 11.394 29.371 ;
     RECT  25.02 29.419 25.038 29.561 ;
     RECT  12.924 28.823 23.166 29.597 ;
     RECT  12.924 29.597 14.562 29.641 ;
     RECT  4.14 29.371 11.394 29.731 ;
     RECT  3.996 29.731 11.394 29.911 ;
     RECT  15.372 29.597 23.166 29.947 ;
     RECT  3.78 29.911 11.394 29.981 ;
     RECT  3.996 29.981 11.394 30.029 ;
     RECT  3.996 30.029 11.322 30.065 ;
     RECT  15.372 29.947 23.382 30.101 ;
     RECT  3.996 30.065 10.797 30.137 ;
     RECT  12.888 29.641 14.562 30.415 ;
     RECT  12.852 30.415 14.562 30.451 ;
     RECT  15.372 30.101 22.698 30.451 ;
     RECT  12.816 30.451 22.698 30.569 ;
     RECT  12.816 30.569 22.446 30.641 ;
     RECT  24.444 30.475 24.462 30.641 ;
     RECT  12.816 30.641 20.358 30.955 ;
     RECT  12.708 30.955 20.358 31.289 ;
     RECT  4.608 30.137 10.797 31.351 ;
     RECT  4.572 31.351 10.797 31.379 ;
     RECT  13.215 31.289 20.358 31.379 ;
     RECT  4.572 31.379 6.03 31.415 ;
     RECT  4.572 31.415 5.922 31.487 ;
     RECT  15.084 31.379 20.358 31.523 ;
     RECT  4.572 31.487 5.397 31.531 ;
     RECT  15.192 31.523 20.358 31.531 ;
     RECT  21.132 30.641 22.446 31.531 ;
     RECT  13.215 31.379 14.13 31.559 ;
     RECT  15.192 31.531 22.446 31.559 ;
     RECT  15.228 31.559 22.446 31.649 ;
     RECT  4.104 31.531 5.397 31.709 ;
     RECT  7.164 31.379 10.797 31.709 ;
     RECT  17.64 31.649 19.89 31.709 ;
     RECT  18.216 31.709 19.89 31.721 ;
     RECT  18.36 31.721 19.89 31.757 ;
     RECT  20.628 31.649 22.446 31.757 ;
     RECT  13.215 31.559 13.95 31.793 ;
     RECT  20.7 31.757 22.446 31.801 ;
     RECT  15.228 31.649 16.506 31.829 ;
     RECT  4.572 31.709 5.397 31.919 ;
     RECT  7.524 31.709 10.797 31.919 ;
     RECT  15.372 31.829 16.197 31.919 ;
     RECT  20.7 31.801 22.482 31.919 ;
     RECT  18.36 31.757 19.386 31.949 ;
     RECT  9.468 31.919 9.702 31.955 ;
     RECT  18.36 31.949 18.897 31.955 ;
     RECT  20.7 31.919 22.41 31.955 ;
     RECT  7.524 31.919 8.514 31.991 ;
     RECT  20.7 31.955 22.05 31.991 ;
     RECT  9.468 31.955 9.666 32.027 ;
     RECT  21.276 31.991 22.05 32.027 ;
     RECT  7.815 31.991 8.514 32.063 ;
     RECT  9.468 32.027 9.486 32.099 ;
     RECT  2.415 28.949 2.697 32.147 ;
     RECT  5.115 31.919 5.397 32.147 ;
     RECT  7.815 32.063 8.097 32.147 ;
     RECT  10.515 31.919 10.797 32.147 ;
     RECT  13.215 31.793 13.497 32.147 ;
     RECT  15.915 31.919 16.197 32.147 ;
     RECT  18.615 31.955 18.897 32.147 ;
     RECT  21.315 32.027 21.597 32.147 ;
     RECT  2.415 32.147 2.505 32.417 ;
     RECT  5.115 32.147 5.205 32.417 ;
     RECT  7.815 32.147 7.905 32.417 ;
     RECT  10.515 32.147 10.605 32.417 ;
     RECT  13.215 32.147 13.305 32.417 ;
     RECT  15.915 32.147 16.005 32.417 ;
     RECT  18.615 32.147 18.705 32.417 ;
     RECT  21.315 32.147 21.405 32.417 ;
    LAYER M4 ;
     RECT  0.108 5.904 0.173 28.632 ;
     RECT  0.173 5.904 0.209 5.928 ;
     RECT  0.173 6.96 0.569 22.296 ;
     RECT  0.569 8.016 2.408 8.04 ;
     RECT  0.569 9.072 2.408 11.736 ;
     RECT  0.569 12.768 2.408 22.296 ;
     RECT  0.173 23.328 2.408 28.632 ;
     RECT  2.408 2.148 2.512 32.412 ;
     RECT  2.512 2.418 2.704 32.142 ;
     RECT  2.704 20.688 2.765 21.24 ;
     RECT  2.704 12.528 2.837 13.848 ;
     RECT  2.704 25.44 2.873 26.088 ;
     RECT  2.704 23.328 3.449 23.88 ;
     RECT  2.873 25.824 3.449 26.088 ;
     RECT  2.704 27.12 3.449 27.96 ;
     RECT  2.837 12.528 3.539 13.704 ;
     RECT  3.539 12.528 3.58 12.792 ;
     RECT  2.704 8.256 3.635 8.808 ;
     RECT  3.449 27.216 3.74 27.96 ;
     RECT  3.733 16.176 3.769 16.2 ;
     RECT  3.74 27.216 3.827 28.872 ;
     RECT  3.74 29.952 3.827 29.976 ;
     RECT  2.704 4.56 3.913 4.584 ;
     RECT  2.765 21.216 3.925 21.24 ;
     RECT  3.769 16.176 3.949 17.064 ;
     RECT  3.769 6.768 3.973 6.792 ;
     RECT  2.704 10.32 4.165 10.344 ;
     RECT  2.704 19.392 4.165 19.416 ;
     RECT  3.913 4.56 4.489 5.064 ;
     RECT  3.769 15.072 4.489 15.096 ;
     RECT  3.949 16.176 4.489 17.64 ;
     RECT  4.057 24.144 4.525 24.168 ;
     RECT  3.449 25.824 4.561 25.896 ;
     RECT  3.827 27.216 4.561 28.2 ;
     RECT  4.489 15.072 4.597 17.64 ;
     RECT  4.165 9.792 4.705 10.344 ;
     RECT  2.704 11.424 4.705 11.448 ;
     RECT  4.597 15.072 4.705 17.688 ;
     RECT  3.925 21.216 4.705 21.72 ;
     RECT  4.705 15.072 4.741 17.736 ;
     RECT  4.165 18.96 4.741 19.416 ;
     RECT  4.489 4.512 4.748 5.064 ;
     RECT  4.741 15.072 4.849 19.416 ;
     RECT  4.849 14.976 4.885 19.416 ;
     RECT  4.705 9.792 4.921 11.448 ;
     RECT  3.58 12.576 4.921 12.792 ;
     RECT  4.885 14.832 4.921 19.416 ;
     RECT  4.705 20.4 4.921 21.72 ;
     RECT  4.669 22.752 4.921 22.776 ;
     RECT  4.921 9.792 4.957 12.792 ;
     RECT  3.973 6.24 4.993 7.176 ;
     RECT  3.635 8.256 4.993 8.28 ;
     RECT  4.237 2.496 5.108 2.52 ;
     RECT  4.748 3.552 5.108 5.064 ;
     RECT  4.993 6.24 5.108 8.28 ;
     RECT  4.957 9.792 5.108 13.08 ;
     RECT  4.921 14.4 5.108 19.416 ;
     RECT  4.921 20.4 5.108 22.776 ;
     RECT  4.525 23.952 5.108 24.168 ;
     RECT  4.561 25.824 5.108 28.2 ;
     RECT  3.781 31.68 5.108 31.704 ;
     RECT  5.108 2.148 5.212 32.412 ;
     RECT  5.212 2.418 5.404 32.142 ;
     RECT  5.404 23.952 5.609 30.648 ;
     RECT  5.609 30.336 5.645 30.648 ;
     RECT  5.404 7.488 5.789 7.944 ;
     RECT  5.404 2.496 5.897 2.52 ;
     RECT  5.645 30.624 5.897 30.648 ;
     RECT  5.404 9.6 5.933 13.08 ;
     RECT  5.404 14.736 6.077 18.264 ;
     RECT  5.609 23.952 6.077 28.968 ;
     RECT  5.933 9.792 6.113 13.08 ;
     RECT  6.113 9.792 6.185 12.84 ;
     RECT  6.077 14.928 6.185 18.264 ;
     RECT  6.077 24.096 6.185 28.968 ;
     RECT  5.404 4.512 6.323 6.216 ;
     RECT  5.404 20.4 6.397 20.904 ;
     RECT  5.404 22.032 6.397 22.776 ;
     RECT  6.185 9.792 6.467 12.792 ;
     RECT  6.397 20.4 6.469 22.776 ;
     RECT  5.789 7.488 6.473 7.752 ;
     RECT  6.185 17.472 6.505 18.264 ;
     RECT  6.323 4.896 6.577 6.216 ;
     RECT  6.577 4.896 6.689 6.84 ;
     RECT  6.185 24.144 6.865 28.968 ;
     RECT  6.829 30.048 6.865 30.072 ;
     RECT  6.505 17.472 7.081 18.696 ;
     RECT  6.469 20.304 7.081 22.776 ;
     RECT  6.865 24.144 7.081 30.072 ;
     RECT  6.185 14.928 7.225 16.44 ;
     RECT  7.081 17.472 7.225 22.776 ;
     RECT  6.467 10.32 7.261 12.792 ;
     RECT  7.081 24.144 7.333 30.12 ;
     RECT  5.404 31.68 7.333 31.704 ;
     RECT  7.225 14.928 7.405 22.776 ;
     RECT  7.333 24.144 7.429 31.704 ;
     RECT  7.261 10.32 7.477 13.32 ;
     RECT  7.405 14.304 7.477 22.776 ;
     RECT  6.689 4.896 7.693 4.92 ;
     RECT  7.693 4.896 7.729 5.016 ;
     RECT  6.689 6.096 7.729 6.84 ;
     RECT  7.729 4.896 7.808 6.84 ;
     RECT  7.477 10.32 7.808 22.776 ;
     RECT  7.429 24.144 7.808 31.944 ;
     RECT  7.808 2.148 7.912 32.412 ;
     RECT  7.912 2.418 8.104 32.142 ;
     RECT  8.104 30.048 8.129 30.12 ;
     RECT  8.104 22.752 8.237 28.968 ;
     RECT  8.104 31.68 8.237 31.704 ;
     RECT  8.237 26.736 8.273 28.968 ;
     RECT  8.273 26.736 8.291 28.92 ;
     RECT  8.104 14.496 8.345 18.216 ;
     RECT  8.291 28.464 8.381 28.92 ;
     RECT  8.345 14.784 8.597 18.216 ;
     RECT  8.104 8.928 8.633 13.32 ;
     RECT  8.104 19.248 8.669 21.432 ;
     RECT  8.129 30.048 8.705 30.072 ;
     RECT  8.633 8.928 8.777 13.224 ;
     RECT  8.104 4.848 9.097 5.592 ;
     RECT  8.104 6.576 9.097 7.368 ;
     RECT  8.104 2.832 9.109 3.72 ;
     RECT  9.097 4.848 9.109 7.368 ;
     RECT  8.291 26.736 9.137 27.096 ;
     RECT  8.777 8.928 9.173 13.176 ;
     RECT  8.597 14.88 9.209 18.216 ;
     RECT  9.173 12.768 9.245 13.176 ;
     RECT  9.173 8.928 9.301 11.688 ;
     RECT  9.109 2.832 9.349 7.368 ;
     RECT  8.669 20.16 9.397 21.432 ;
     RECT  9.349 2.832 9.433 7.416 ;
     RECT  9.301 8.544 9.461 11.688 ;
     RECT  9.397 20.16 9.484 21.768 ;
     RECT  9.433 6.288 9.529 7.416 ;
     RECT  9.461 8.544 9.529 9 ;
     RECT  9.137 26.736 9.565 26.76 ;
     RECT  8.381 28.464 9.709 28.824 ;
     RECT  9.433 2.832 9.889 4.968 ;
     RECT  8.237 22.752 10.069 25.512 ;
     RECT  9.709 28.368 10.213 29.352 ;
     RECT  9.565 26.592 10.261 26.76 ;
     RECT  10.213 27.888 10.261 29.352 ;
     RECT  10.261 26.592 10.277 29.352 ;
     RECT  9.461 10.32 10.321 11.688 ;
     RECT  9.245 12.768 10.321 12.936 ;
     RECT  10.277 26.592 10.429 29.688 ;
     RECT  9.889 2.496 10.508 4.968 ;
     RECT  9.529 6.288 10.508 9 ;
     RECT  10.321 10.32 10.508 12.936 ;
     RECT  9.209 14.928 10.508 18.216 ;
     RECT  9.484 20.16 10.508 21.432 ;
     RECT  10.069 22.464 10.508 25.512 ;
     RECT  10.429 26.544 10.508 29.688 ;
     RECT  10.508 2.148 10.612 32.412 ;
     RECT  10.612 2.148 10.804 32.142 ;
     RECT  10.804 29.568 10.829 29.88 ;
     RECT  10.804 14.928 10.865 17.064 ;
     RECT  10.804 2.148 10.969 2.52 ;
     RECT  10.804 26.544 11.009 26.616 ;
     RECT  10.804 21.6 11.045 24.936 ;
     RECT  10.969 1.728 11.267 2.52 ;
     RECT  11.009 26.544 11.297 26.568 ;
     RECT  11.045 21.6 11.411 22.872 ;
     RECT  11.411 21.648 11.477 22.872 ;
     RECT  11.477 21.648 11.549 22.824 ;
     RECT  10.804 9.792 11.585 12.792 ;
     RECT  10.804 7.056 11.657 7.416 ;
     RECT  10.865 15.024 11.657 17.064 ;
     RECT  10.804 4.224 11.729 5.784 ;
     RECT  11.045 24.096 11.837 24.936 ;
     RECT  11.657 15.456 11.945 17.064 ;
     RECT  10.804 8.448 11.977 8.616 ;
     RECT  11.585 9.792 11.977 12.552 ;
     RECT  11.837 24.096 12.013 24.696 ;
     RECT  11.267 2.496 12.089 2.52 ;
     RECT  11.945 15.744 12.181 17.064 ;
     RECT  10.804 18.144 12.181 18.168 ;
     RECT  11.657 7.104 12.445 7.416 ;
     RECT  11.977 8.448 12.445 12.552 ;
     RECT  11.729 4.8 12.913 5.784 ;
     RECT  12.445 7.104 12.913 12.552 ;
     RECT  12.013 23.952 12.997 24.696 ;
     RECT  12.985 25.68 12.997 26.568 ;
     RECT  12.181 15.744 13.093 18.168 ;
     RECT  11.549 21.648 13.093 22.248 ;
     RECT  12.913 4.8 13.208 12.552 ;
     RECT  12.757 14.208 13.208 14.232 ;
     RECT  13.093 15.456 13.208 18.168 ;
     RECT  12.121 19.296 13.208 19.32 ;
     RECT  13.093 21.216 13.208 22.248 ;
     RECT  12.997 23.952 13.208 26.568 ;
     RECT  10.804 27.648 13.208 27.912 ;
     RECT  10.829 29.856 13.208 29.88 ;
     RECT  13.208 2.148 13.312 32.412 ;
     RECT  13.312 2.418 13.504 32.142 ;
     RECT  13.504 4.656 13.529 7.416 ;
     RECT  13.504 28.224 13.637 30.456 ;
     RECT  13.504 14.208 13.709 26.76 ;
     RECT  13.504 8.448 13.745 12.792 ;
     RECT  13.709 18.144 13.853 26.76 ;
     RECT  13.853 20.4 14.069 26.76 ;
     RECT  13.709 14.208 14.105 16.92 ;
     RECT  14.105 14.448 14.285 16.92 ;
     RECT  13.637 29.856 14.285 30.456 ;
     RECT  13.529 4.656 14.357 4.68 ;
     RECT  14.285 15.552 14.357 16.92 ;
     RECT  14.069 25.728 14.435 26.76 ;
     RECT  13.529 5.76 14.533 7.416 ;
     RECT  14.425 1.728 14.723 1.752 ;
     RECT  14.357 15.744 14.749 16.92 ;
     RECT  14.435 26.304 14.749 26.76 ;
     RECT  14.749 15.744 14.785 17.16 ;
     RECT  13.853 18.144 14.785 19.32 ;
     RECT  14.069 20.4 14.819 24.696 ;
     RECT  13.745 11.712 14.825 12.792 ;
     RECT  14.819 22.8 14.825 24.696 ;
     RECT  14.533 5.568 14.857 7.416 ;
     RECT  13.745 8.448 14.857 10.728 ;
     RECT  14.749 26.304 14.857 26.904 ;
     RECT  14.857 5.568 14.861 10.728 ;
     RECT  14.861 7.248 14.965 10.728 ;
     RECT  14.825 11.712 14.965 11.976 ;
     RECT  14.785 15.744 15.037 19.32 ;
     RECT  14.819 20.4 15.037 21.768 ;
     RECT  14.857 26.304 15.037 26.952 ;
     RECT  13.637 28.224 15.037 28.488 ;
     RECT  14.285 29.856 15.289 30.36 ;
     RECT  15.253 31.392 15.289 31.416 ;
     RECT  15.541 13.104 15.649 13.128 ;
     RECT  14.285 14.448 15.649 14.472 ;
     RECT  15.037 15.744 15.757 21.768 ;
     RECT  13.504 3.408 15.908 3.432 ;
     RECT  14.861 5.568 15.908 5.736 ;
     RECT  14.965 7.248 15.908 11.976 ;
     RECT  15.649 13.104 15.908 14.472 ;
     RECT  15.757 15.504 15.908 21.768 ;
     RECT  14.825 22.992 15.908 24.696 ;
     RECT  15.037 26.304 15.908 28.488 ;
     RECT  15.289 29.856 15.908 31.416 ;
     RECT  15.908 2.148 16.012 32.412 ;
     RECT  16.012 2.418 16.204 32.142 ;
     RECT  16.204 10.896 16.445 18.168 ;
     RECT  16.445 13.872 16.517 18.168 ;
     RECT  16.517 13.872 16.589 17.4 ;
     RECT  16.445 10.896 16.697 12.504 ;
     RECT  16.204 19.248 17.057 20.088 ;
     RECT  16.204 26.496 17.075 31.416 ;
     RECT  16.204 3.408 17.123 5.688 ;
     RECT  17.123 3.984 17.197 5.688 ;
     RECT  17.075 26.832 17.201 31.416 ;
     RECT  16.204 21.216 17.317 21.96 ;
     RECT  16.204 7.392 17.341 9.816 ;
     RECT  16.697 11.184 17.381 12.504 ;
     RECT  17.341 6.816 17.459 9.816 ;
     RECT  17.201 27.696 17.629 31.416 ;
     RECT  16.589 14.448 17.804 17.4 ;
     RECT  17.381 12.48 17.845 12.504 ;
     RECT  16.204 24.096 17.881 25.32 ;
     RECT  17.057 19.248 17.917 19.32 ;
     RECT  17.381 11.184 17.953 11.256 ;
     RECT  17.804 13.872 17.989 17.4 ;
     RECT  17.917 18.96 18.025 19.32 ;
     RECT  17.317 20.4 18.037 21.96 ;
     RECT  17.459 7.632 18.097 9.816 ;
     RECT  17.953 10.896 18.097 11.256 ;
     RECT  17.989 13.824 18.097 17.4 ;
     RECT  18.025 18.96 18.097 19.368 ;
     RECT  18.037 20.4 18.313 22.296 ;
     RECT  17.197 3.984 18.469 5.832 ;
     RECT  18.133 2.496 18.493 2.52 ;
     RECT  18.469 3.552 18.493 5.832 ;
     RECT  17.629 27.696 18.493 31.704 ;
     RECT  18.493 27.648 18.529 31.704 ;
     RECT  18.493 2.496 18.608 5.832 ;
     RECT  18.097 7.632 18.608 11.256 ;
     RECT  17.845 12.48 18.608 12.552 ;
     RECT  18.097 13.824 18.608 19.368 ;
     RECT  18.313 20.4 18.608 22.584 ;
     RECT  17.881 23.856 18.608 25.32 ;
     RECT  18.529 27.072 18.608 31.704 ;
     RECT  18.608 2.148 18.712 32.412 ;
     RECT  18.712 2.418 18.904 32.142 ;
     RECT  18.904 5.04 19.037 12.504 ;
     RECT  18.904 14.832 19.043 22.2 ;
     RECT  18.904 23.28 19.045 31.944 ;
     RECT  19.037 5.04 19.181 12.36 ;
     RECT  19.045 23.28 19.181 29.016 ;
     RECT  19.181 27.12 19.217 29.016 ;
     RECT  19.181 5.04 19.325 12.024 ;
     RECT  19.217 27.168 19.397 29.016 ;
     RECT  19.043 14.832 19.433 19.032 ;
     RECT  19.043 20.064 19.433 22.2 ;
     RECT  19.325 5.04 19.469 7.416 ;
     RECT  19.433 14.832 19.613 18.792 ;
     RECT  18.904 2.496 19.649 2.52 ;
     RECT  19.613 14.832 19.685 18.744 ;
     RECT  19.685 14.832 19.829 18.696 ;
     RECT  18.904 13.68 19.897 13.848 ;
     RECT  19.829 14.832 19.897 18.024 ;
     RECT  19.045 30.048 19.937 31.944 ;
     RECT  19.937 30.048 20.045 30.84 ;
     RECT  19.469 5.04 20.185 6.888 ;
     RECT  19.325 8.544 20.185 12.024 ;
     RECT  20.185 8.544 20.221 12.12 ;
     RECT  19.897 13.68 20.221 18.024 ;
     RECT  19.433 20.4 20.225 22.2 ;
     RECT  20.185 4.992 20.389 6.888 ;
     RECT  20.221 8.544 20.473 12.552 ;
     RECT  19.181 23.28 20.473 26.136 ;
     RECT  20.045 30.048 20.509 30.408 ;
     RECT  20.225 21.216 20.581 22.2 ;
     RECT  20.473 23.28 20.581 26.328 ;
     RECT  20.473 8.448 20.617 12.552 ;
     RECT  20.221 13.536 20.617 18.024 ;
     RECT  20.617 8.448 21.085 18.024 ;
     RECT  20.581 21.216 21.085 26.328 ;
     RECT  19.397 28.32 21.109 29.016 ;
     RECT  20.509 30 21.109 30.408 ;
     RECT  19.937 31.92 21.109 31.944 ;
     RECT  20.389 3.6 21.308 6.888 ;
     RECT  21.085 8.448 21.308 18.216 ;
     RECT  21.157 20.064 21.308 20.088 ;
     RECT  21.085 21.216 21.308 26.52 ;
     RECT  21.109 27.888 21.308 30.408 ;
     RECT  21.109 31.92 21.308 31.992 ;
     RECT  21.308 2.148 21.412 32.412 ;
     RECT  21.412 2.418 21.604 32.142 ;
     RECT  21.604 25.776 21.629 26.088 ;
     RECT  21.604 8.544 21.665 12.552 ;
     RECT  21.604 22.752 21.665 23.88 ;
     RECT  21.629 25.776 21.737 25.8 ;
     RECT  21.665 22.752 21.809 22.776 ;
     RECT  21.604 27.888 21.845 28.776 ;
     RECT  21.604 15.216 21.989 16.872 ;
     RECT  21.845 27.984 22.061 28.776 ;
     RECT  21.665 8.784 22.205 12.552 ;
     RECT  22.061 27.984 22.241 28.296 ;
     RECT  22.205 9.024 22.313 12.552 ;
     RECT  22.241 27.984 22.349 28.008 ;
     RECT  21.665 23.856 22.385 23.88 ;
     RECT  21.989 15.216 22.565 16.056 ;
     RECT  22.313 9.024 22.709 11.448 ;
     RECT  22.709 9.072 22.835 11.448 ;
     RECT  22.835 9.792 22.889 11.448 ;
     RECT  22.313 12.528 22.925 12.552 ;
     RECT  22.889 10.32 23.033 11.448 ;
     RECT  23.033 10.32 23.069 10.584 ;
     RECT  22.565 15.216 23.353 15.72 ;
     RECT  23.069 10.56 23.357 10.584 ;
     RECT  23.353 24.672 23.929 25.224 ;
     RECT  23.353 16.752 24.289 16.776 ;
     RECT  23.353 29.952 24.433 29.976 ;
     RECT  23.353 7.248 24.469 7.272 ;
     RECT  23.929 13.056 24.469 13.608 ;
     RECT  23.353 15.168 24.469 15.72 ;
     RECT  24.289 16.752 24.469 17.304 ;
     RECT  23.353 18.336 24.469 18.888 ;
     RECT  24.433 26.256 24.469 26.28 ;
     RECT  24.469 13.056 24.505 14.136 ;
     RECT  24.469 15.168 24.505 18.888 ;
     RECT  23.353 23.088 24.505 23.112 ;
     RECT  23.929 24.144 24.505 25.224 ;
     RECT  24.505 10.944 24.541 12.024 ;
     RECT  24.505 22.56 24.577 25.224 ;
     RECT  24.469 26.256 24.577 26.808 ;
     RECT  24.469 28.368 25.009 28.392 ;
     RECT  24.433 29.952 25.009 30.504 ;
     RECT  23.605 5.136 25.045 5.16 ;
     RECT  24.469 6.72 25.045 7.272 ;
     RECT  25.009 9.36 25.045 9.384 ;
     RECT  24.541 10.416 25.045 12.024 ;
     RECT  24.577 22.56 25.045 26.808 ;
     RECT  25.045 9.36 25.081 12.024 ;
     RECT  24.505 13.056 25.081 18.888 ;
     RECT  24.577 19.92 25.081 19.944 ;
     RECT  25.045 20.976 25.081 21 ;
     RECT  25.045 22.032 25.081 26.808 ;
     RECT  25.009 27.84 25.081 28.392 ;
     RECT  25.009 29.424 25.081 30.504 ;
     RECT  23.605 4.08 25.729 4.104 ;
     RECT  25.045 5.136 25.729 7.8 ;
     RECT  25.081 9.36 25.729 30.504 ;
     RECT  25.729 4.08 25.788 30.504 ;
     RECT  25.788 7.968 25.841 7.992 ;
    LAYER M5 ;
     RECT  11.232 0.08 11.256 1.763 ;
     RECT  14.688 0.08 14.712 1.763 ;
     RECT  12.96 0.08 12.984 2.137 ;
     RECT  2.4 2.137 2.52 2.151 ;
     RECT  5.1 2.137 5.22 2.151 ;
     RECT  7.8 2.137 7.92 2.151 ;
     RECT  12.96 2.137 13.32 2.151 ;
     RECT  15.9 2.137 16.02 2.151 ;
     RECT  18.6 2.137 18.72 2.151 ;
     RECT  21.3 2.137 21.42 2.151 ;
     RECT  5.1 2.151 5.412 2.485 ;
     RECT  18.6 2.151 18.912 2.485 ;
     RECT  15.9 2.151 16.212 3.397 ;
     RECT  4.8 2.485 5.412 3.587 ;
     RECT  21.3 2.151 21.612 3.589 ;
     RECT  9.36 2.821 9.384 3.685 ;
     RECT  9.12 3.685 9.384 3.731 ;
     RECT  5.1 3.587 5.412 4.501 ;
     RECT  9.12 3.731 9.144 4.547 ;
     RECT  15.9 3.397 17.112 4.595 ;
     RECT  12.96 2.151 13.512 4.645 ;
     RECT  10.5 2.137 10.812 4.741 ;
     RECT  18.48 2.485 18.912 4.837 ;
     RECT  5.1 4.501 6.312 4.931 ;
     RECT  10.5 4.741 11.64 4.933 ;
     RECT  17.808 4.837 18.912 5.029 ;
     RECT  20.4 3.589 21.612 5.075 ;
     RECT  15.9 4.595 16.212 5.701 ;
     RECT  9.36 5.125 9.384 5.747 ;
     RECT  17.808 5.029 19.368 5.843 ;
     RECT  17.808 5.843 19.032 6.131 ;
     RECT  12.96 4.645 13.704 6.229 ;
     RECT  10.5 4.933 11.784 6.613 ;
     RECT  17.808 6.131 18.912 6.805 ;
     RECT  3.984 6.229 4.008 7.187 ;
     RECT  12.96 6.229 14.28 7.187 ;
     RECT  7.8 2.151 8.112 7.333 ;
     RECT  2.4 2.151 2.712 8.245 ;
     RECT  10.368 6.613 11.784 8.435 ;
     RECT  7.8 7.333 8.952 8.533 ;
     RECT  2.4 8.245 3.624 8.819 ;
     RECT  17.424 6.805 18.912 8.869 ;
     RECT  15.696 5.701 16.212 9.013 ;
     RECT  14.784 9.013 16.212 9.061 ;
     RECT  17.424 8.869 19.32 9.061 ;
     RECT  14.784 9.061 19.32 9.155 ;
     RECT  14.784 9.155 19.272 9.395 ;
     RECT  7.8 8.533 9.336 9.491 ;
     RECT  14.784 9.395 17.064 9.539 ;
     RECT  10.5 8.435 11.784 10.213 ;
     RECT  12.96 7.187 13.512 10.213 ;
     RECT  22.8 9.061 22.824 10.307 ;
     RECT  6.432 9.781 6.456 10.883 ;
     RECT  9.36 9.589 9.384 10.931 ;
     RECT  10.5 10.213 13.512 11.699 ;
     RECT  11.952 11.699 13.512 11.795 ;
     RECT  14.784 9.539 14.808 11.987 ;
     RECT  18.6 9.395 19.272 12.035 ;
     RECT  21.3 5.075 21.612 12.181 ;
     RECT  2.4 8.819 2.712 12.517 ;
     RECT  5.1 4.931 5.412 12.517 ;
     RECT  15.9 9.539 17.064 12.517 ;
     RECT  18.6 12.035 19.224 12.517 ;
     RECT  12.24 11.795 13.512 12.757 ;
     RECT  4.992 12.517 5.412 12.803 ;
     RECT  2.4 12.517 3.528 13.715 ;
     RECT  15.9 12.517 19.224 13.715 ;
     RECT  21.168 12.181 21.612 14.245 ;
     RECT  7.8 9.491 8.112 14.773 ;
     RECT  6.528 11.653 6.552 15.443 ;
     RECT  12.24 12.757 13.656 15.443 ;
     RECT  10.5 11.699 10.812 15.541 ;
     RECT  15.9 13.715 18.912 15.733 ;
     RECT  20.256 14.245 21.612 15.733 ;
     RECT  15.9 15.733 21.612 15.827 ;
     RECT  18.144 15.827 21.612 16.019 ;
     RECT  18.144 16.019 20.28 16.307 ;
     RECT  10.08 15.541 10.812 16.931 ;
     RECT  7.8 14.773 8.568 16.981 ;
     RECT  7.8 16.981 9.096 17.123 ;
     RECT  12.24 15.443 13.608 17.365 ;
     RECT  12.192 17.365 13.608 17.411 ;
     RECT  13.2 17.411 13.608 17.459 ;
     RECT  5.1 12.803 5.412 17.605 ;
     RECT  15.9 15.827 17.064 17.605 ;
     RECT  10.5 16.931 10.812 18.133 ;
     RECT  12.192 17.411 12.216 18.133 ;
     RECT  21.3 16.019 21.612 18.181 ;
     RECT  18.144 16.307 19.32 18.851 ;
     RECT  18.144 18.851 19.08 19.333 ;
     RECT  4.992 17.605 5.412 19.427 ;
     RECT  7.8 17.123 8.616 20.293 ;
     RECT  7.8 20.293 8.664 20.821 ;
     RECT  18.048 19.333 19.08 20.869 ;
     RECT  15.792 17.605 17.064 21.013 ;
     RECT  18.048 20.869 19.176 21.013 ;
     RECT  15.792 21.013 19.176 21.205 ;
     RECT  15.408 21.205 19.176 21.397 ;
     RECT  10.5 18.133 12.216 21.683 ;
     RECT  3.936 21.205 3.96 21.731 ;
     RECT  13.2 17.459 13.512 21.733 ;
     RECT  7.8 20.821 9.432 21.779 ;
     RECT  15.408 21.397 19.416 21.779 ;
     RECT  13.2 21.733 14.424 21.829 ;
     RECT  21.168 18.181 21.612 22.741 ;
     RECT  7.8 21.779 8.664 22.787 ;
     RECT  10.5 21.683 11.4 22.835 ;
     RECT  10.5 22.835 11.208 22.883 ;
     RECT  20.928 22.741 21.612 23.077 ;
     RECT  10.5 22.883 10.968 23.411 ;
     RECT  13.2 21.829 14.808 23.555 ;
     RECT  15.9 21.779 19.416 23.891 ;
     RECT  7.8 22.787 8.52 24.131 ;
     RECT  13.2 23.555 14.424 24.229 ;
     RECT  20.592 23.077 21.612 24.469 ;
     RECT  10.5 23.411 10.812 24.661 ;
     RECT  15.9 23.891 17.352 24.995 ;
     RECT  15.9 24.995 17.064 25.139 ;
     RECT  13.008 24.229 14.424 25.715 ;
     RECT  18.6 23.891 19.416 25.763 ;
     RECT  20.496 24.469 21.612 26.339 ;
     RECT  15.9 25.139 16.212 26.485 ;
     RECT  7.8 24.131 8.28 26.773 ;
     RECT  2.4 13.715 2.712 27.205 ;
     RECT  7.68 26.773 8.28 27.683 ;
     RECT  10.272 24.661 10.812 27.877 ;
     RECT  2.4 27.205 3.432 27.971 ;
     RECT  13.2 25.715 14.424 28.259 ;
     RECT  18.6 25.763 19.32 28.355 ;
     RECT  18.6 28.355 19.032 28.453 ;
     RECT  7.8 27.683 8.28 28.931 ;
     RECT  7.8 28.931 8.112 28.933 ;
     RECT  10.224 27.877 10.812 28.979 ;
     RECT  18.144 28.453 19.032 29.171 ;
     RECT  10.32 28.979 10.812 29.699 ;
     RECT  15.9 26.485 17.064 29.893 ;
     RECT  18.144 29.171 18.912 29.893 ;
     RECT  15.9 29.893 18.912 29.987 ;
     RECT  17.232 29.987 18.912 30.803 ;
     RECT  18.144 30.803 18.912 30.851 ;
     RECT  7.536 28.933 8.112 30.997 ;
     RECT  3.792 28.837 3.816 31.715 ;
     RECT  7.44 30.997 8.112 31.955 ;
     RECT  21.12 26.339 21.612 32.003 ;
     RECT  2.4 27.971 2.712 32.409 ;
     RECT  5.1 19.427 5.412 32.409 ;
     RECT  7.8 31.955 8.112 32.409 ;
     RECT  10.5 29.699 10.812 32.409 ;
     RECT  13.2 28.259 13.512 32.409 ;
     RECT  15.9 29.987 16.212 32.409 ;
     RECT  18.6 30.851 18.912 32.409 ;
     RECT  21.3 32.003 21.612 32.409 ;
     RECT  2.4 32.409 2.52 32.423 ;
     RECT  5.1 32.409 5.22 32.423 ;
     RECT  7.8 32.409 7.92 32.423 ;
     RECT  10.5 32.409 10.62 32.423 ;
     RECT  13.2 32.409 13.32 32.423 ;
     RECT  15.9 32.409 16.02 32.423 ;
     RECT  18.6 32.409 18.72 32.423 ;
     RECT  21.3 32.409 21.42 32.423 ;
  END
END qkd_d2d_cal_seq_pin_bc4
END LIBRARY
